VERSION 5.7 ;
  NOWIREEXTENSIONATPIN ON ;
  DIVIDERCHAR "/" ;
  BUSBITCHARS "[]" ;
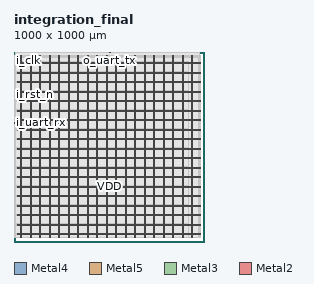
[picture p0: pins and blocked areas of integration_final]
MACRO integration_final
  CLASS BLOCK ;
  FOREIGN integration_final ;
  ORIGIN 0.000 0.000 ;
  SIZE 1000.000 BY 1000.000 ;
  PIN VDD
    DIRECTION INOUT ;
    USE POWER ;
    PORT
      LAYER Metal4 ;
        RECT 35.680 23.220 37.280 980.300 ;
    END
    PORT
      LAYER Metal4 ;
        RECT 85.680 23.220 87.280 980.300 ;
    END
    PORT
      LAYER Metal4 ;
        RECT 135.680 23.220 137.280 980.300 ;
    END
    PORT
      LAYER Metal4 ;
        RECT 185.680 23.220 187.280 980.300 ;
    END
    PORT
      LAYER Metal4 ;
        RECT 235.680 23.220 237.280 980.300 ;
    END
    PORT
      LAYER Metal4 ;
        RECT 285.680 23.220 287.280 980.300 ;
    END
    PORT
      LAYER Metal4 ;
        RECT 335.680 23.220 337.280 980.300 ;
    END
    PORT
      LAYER Metal4 ;
        RECT 385.680 23.220 387.280 980.300 ;
    END
    PORT
      LAYER Metal4 ;
        RECT 435.680 23.220 437.280 980.300 ;
    END
    PORT
      LAYER Metal4 ;
        RECT 485.680 23.220 487.280 980.300 ;
    END
    PORT
      LAYER Metal4 ;
        RECT 535.680 23.220 537.280 980.300 ;
    END
    PORT
      LAYER Metal4 ;
        RECT 585.680 23.220 587.280 980.300 ;
    END
    PORT
      LAYER Metal4 ;
        RECT 635.680 23.220 637.280 980.300 ;
    END
    PORT
      LAYER Metal4 ;
        RECT 685.680 23.220 687.280 980.300 ;
    END
    PORT
      LAYER Metal4 ;
        RECT 735.680 23.220 737.280 980.300 ;
    END
    PORT
      LAYER Metal4 ;
        RECT 785.680 23.220 787.280 980.300 ;
    END
    PORT
      LAYER Metal4 ;
        RECT 835.680 23.220 837.280 980.300 ;
    END
    PORT
      LAYER Metal4 ;
        RECT 885.680 23.220 887.280 980.300 ;
    END
    PORT
      LAYER Metal4 ;
        RECT 935.680 23.220 937.280 980.300 ;
    END
    PORT
      LAYER Metal5 ;
        RECT 20.160 39.370 980.000 40.970 ;
    END
    PORT
      LAYER Metal5 ;
        RECT 20.160 89.370 980.000 90.970 ;
    END
    PORT
      LAYER Metal5 ;
        RECT 20.160 139.370 980.000 140.970 ;
    END
    PORT
      LAYER Metal5 ;
        RECT 20.160 189.370 980.000 190.970 ;
    END
    PORT
      LAYER Metal5 ;
        RECT 20.160 239.370 980.000 240.970 ;
    END
    PORT
      LAYER Metal5 ;
        RECT 20.160 289.370 980.000 290.970 ;
    END
    PORT
      LAYER Metal5 ;
        RECT 20.160 339.370 980.000 340.970 ;
    END
    PORT
      LAYER Metal5 ;
        RECT 20.160 389.370 980.000 390.970 ;
    END
    PORT
      LAYER Metal5 ;
        RECT 20.160 439.370 980.000 440.970 ;
    END
    PORT
      LAYER Metal5 ;
        RECT 20.160 489.370 980.000 490.970 ;
    END
    PORT
      LAYER Metal5 ;
        RECT 20.160 539.370 980.000 540.970 ;
    END
    PORT
      LAYER Metal5 ;
        RECT 20.160 589.370 980.000 590.970 ;
    END
    PORT
      LAYER Metal5 ;
        RECT 20.160 639.370 980.000 640.970 ;
    END
    PORT
      LAYER Metal5 ;
        RECT 20.160 689.370 980.000 690.970 ;
    END
    PORT
      LAYER Metal5 ;
        RECT 20.160 739.370 980.000 740.970 ;
    END
    PORT
      LAYER Metal5 ;
        RECT 20.160 789.370 980.000 790.970 ;
    END
    PORT
      LAYER Metal5 ;
        RECT 20.160 839.370 980.000 840.970 ;
    END
    PORT
      LAYER Metal5 ;
        RECT 20.160 889.370 980.000 890.970 ;
    END
    PORT
      LAYER Metal5 ;
        RECT 20.160 939.370 980.000 940.970 ;
    END
  END VDD
  PIN VSS
    DIRECTION INOUT ;
    USE GROUND ;
    PORT
      LAYER Metal4 ;
        RECT 38.880 23.220 40.480 980.300 ;
    END
    PORT
      LAYER Metal4 ;
        RECT 88.880 23.220 90.480 980.300 ;
    END
    PORT
      LAYER Metal4 ;
        RECT 138.880 23.220 140.480 980.300 ;
    END
    PORT
      LAYER Metal4 ;
        RECT 188.880 23.220 190.480 980.300 ;
    END
    PORT
      LAYER Metal4 ;
        RECT 238.880 23.220 240.480 980.300 ;
    END
    PORT
      LAYER Metal4 ;
        RECT 288.880 23.220 290.480 980.300 ;
    END
    PORT
      LAYER Metal4 ;
        RECT 338.880 23.220 340.480 980.300 ;
    END
    PORT
      LAYER Metal4 ;
        RECT 388.880 23.220 390.480 980.300 ;
    END
    PORT
      LAYER Metal4 ;
        RECT 438.880 23.220 440.480 980.300 ;
    END
    PORT
      LAYER Metal4 ;
        RECT 488.880 23.220 490.480 980.300 ;
    END
    PORT
      LAYER Metal4 ;
        RECT 538.880 23.220 540.480 980.300 ;
    END
    PORT
      LAYER Metal4 ;
        RECT 588.880 23.220 590.480 980.300 ;
    END
    PORT
      LAYER Metal4 ;
        RECT 638.880 23.220 640.480 980.300 ;
    END
    PORT
      LAYER Metal4 ;
        RECT 688.880 23.220 690.480 980.300 ;
    END
    PORT
      LAYER Metal4 ;
        RECT 738.880 23.220 740.480 980.300 ;
    END
    PORT
      LAYER Metal4 ;
        RECT 788.880 23.220 790.480 980.300 ;
    END
    PORT
      LAYER Metal4 ;
        RECT 838.880 23.220 840.480 980.300 ;
    END
    PORT
      LAYER Metal4 ;
        RECT 888.880 23.220 890.480 980.300 ;
    END
    PORT
      LAYER Metal4 ;
        RECT 938.880 23.220 940.480 980.300 ;
    END
    PORT
      LAYER Metal5 ;
        RECT 20.160 42.570 980.000 44.170 ;
    END
    PORT
      LAYER Metal5 ;
        RECT 20.160 92.570 980.000 94.170 ;
    END
    PORT
      LAYER Metal5 ;
        RECT 20.160 142.570 980.000 144.170 ;
    END
    PORT
      LAYER Metal5 ;
        RECT 20.160 192.570 980.000 194.170 ;
    END
    PORT
      LAYER Metal5 ;
        RECT 20.160 242.570 980.000 244.170 ;
    END
    PORT
      LAYER Metal5 ;
        RECT 20.160 292.570 980.000 294.170 ;
    END
    PORT
      LAYER Metal5 ;
        RECT 20.160 342.570 980.000 344.170 ;
    END
    PORT
      LAYER Metal5 ;
        RECT 20.160 392.570 980.000 394.170 ;
    END
    PORT
      LAYER Metal5 ;
        RECT 20.160 442.570 980.000 444.170 ;
    END
    PORT
      LAYER Metal5 ;
        RECT 20.160 492.570 980.000 494.170 ;
    END
    PORT
      LAYER Metal5 ;
        RECT 20.160 542.570 980.000 544.170 ;
    END
    PORT
      LAYER Metal5 ;
        RECT 20.160 592.570 980.000 594.170 ;
    END
    PORT
      LAYER Metal5 ;
        RECT 20.160 642.570 980.000 644.170 ;
    END
    PORT
      LAYER Metal5 ;
        RECT 20.160 692.570 980.000 694.170 ;
    END
    PORT
      LAYER Metal5 ;
        RECT 20.160 742.570 980.000 744.170 ;
    END
    PORT
      LAYER Metal5 ;
        RECT 20.160 792.570 980.000 794.170 ;
    END
    PORT
      LAYER Metal5 ;
        RECT 20.160 842.570 980.000 844.170 ;
    END
    PORT
      LAYER Metal5 ;
        RECT 20.160 892.570 980.000 894.170 ;
    END
    PORT
      LAYER Metal5 ;
        RECT 20.160 942.570 980.000 944.170 ;
    END
  END VSS
  PIN i_clk
    DIRECTION INPUT ;
    USE SIGNAL ;
    ANTENNAGATEAREA 4.738000 ;
    ANTENNADIFFAREA 0.410400 ;
    PORT
      LAYER Metal3 ;
        RECT 0.000 974.400 0.560 974.960 ;
    END
  END i_clk
  PIN i_rst_n
    DIRECTION INPUT ;
    USE SIGNAL ;
    ANTENNAGATEAREA 1.183000 ;
    ANTENNADIFFAREA 0.410400 ;
    PORT
      LAYER Metal3 ;
        RECT 0.000 773.920 0.560 774.480 ;
    END
  END i_rst_n
  PIN i_uart_rx
    DIRECTION INPUT ;
    USE SIGNAL ;
    ANTENNAGATEAREA 0.741000 ;
    ANTENNADIFFAREA 0.410400 ;
    PORT
      LAYER Metal3 ;
        RECT 0.000 626.080 0.560 626.640 ;
    END
  END i_uart_rx
  PIN o_uart_tx
    DIRECTION OUTPUT ;
    USE SIGNAL ;
    ANTENNADIFFAREA 0.897600 ;
    PORT
      LAYER Metal2 ;
        RECT 505.120 999.440 505.680 1000.000 ;
    END
  END o_uart_tx
  OBS
      LAYER Nwell ;
        RECT 19.730 23.090 980.430 980.430 ;
      LAYER Metal1 ;
        RECT 20.160 23.220 980.000 980.300 ;
      LAYER Metal2 ;
        RECT 7.420 999.140 504.820 999.440 ;
        RECT 505.980 999.140 978.740 999.440 ;
        RECT 7.420 21.930 978.740 999.140 ;
      LAYER Metal3 ;
        RECT 0.560 975.260 978.790 980.140 ;
        RECT 0.860 974.100 978.790 975.260 ;
        RECT 0.560 774.780 978.790 974.100 ;
        RECT 0.860 773.620 978.790 774.780 ;
        RECT 0.560 626.940 978.790 773.620 ;
        RECT 0.860 625.780 978.790 626.940 ;
        RECT 0.560 21.980 978.790 625.780 ;
      LAYER Metal4 ;
        RECT 5.740 25.290 35.380 971.510 ;
        RECT 37.580 25.290 38.580 971.510 ;
        RECT 40.780 25.290 85.380 971.510 ;
        RECT 87.580 25.290 88.580 971.510 ;
        RECT 90.780 25.290 135.380 971.510 ;
        RECT 137.580 25.290 138.580 971.510 ;
        RECT 140.780 25.290 185.380 971.510 ;
        RECT 187.580 25.290 188.580 971.510 ;
        RECT 190.780 25.290 235.380 971.510 ;
        RECT 237.580 25.290 238.580 971.510 ;
        RECT 240.780 25.290 285.380 971.510 ;
        RECT 287.580 25.290 288.580 971.510 ;
        RECT 290.780 25.290 335.380 971.510 ;
        RECT 337.580 25.290 338.580 971.510 ;
        RECT 340.780 25.290 385.380 971.510 ;
        RECT 387.580 25.290 388.580 971.510 ;
        RECT 390.780 25.290 435.380 971.510 ;
        RECT 437.580 25.290 438.580 971.510 ;
        RECT 440.780 25.290 485.380 971.510 ;
        RECT 487.580 25.290 488.580 971.510 ;
        RECT 490.780 25.290 535.380 971.510 ;
        RECT 537.580 25.290 538.580 971.510 ;
        RECT 540.780 25.290 585.380 971.510 ;
        RECT 587.580 25.290 588.580 971.510 ;
        RECT 590.780 25.290 635.380 971.510 ;
        RECT 637.580 25.290 638.580 971.510 ;
        RECT 640.780 25.290 685.380 971.510 ;
        RECT 687.580 25.290 688.580 971.510 ;
        RECT 690.780 25.290 735.380 971.510 ;
        RECT 737.580 25.290 738.580 971.510 ;
        RECT 740.780 25.290 785.380 971.510 ;
        RECT 787.580 25.290 788.580 971.510 ;
        RECT 790.780 25.290 835.380 971.510 ;
        RECT 837.580 25.290 838.580 971.510 ;
        RECT 840.780 25.290 885.380 971.510 ;
        RECT 887.580 25.290 888.580 971.510 ;
        RECT 890.780 25.290 935.380 971.510 ;
        RECT 937.580 25.290 938.580 971.510 ;
        RECT 940.780 25.290 971.460 971.510 ;
      LAYER Metal5 ;
        RECT 5.660 944.770 919.460 949.270 ;
        RECT 5.660 941.970 19.560 944.770 ;
        RECT 5.660 941.570 919.460 941.970 ;
        RECT 5.660 938.770 19.560 941.570 ;
        RECT 5.660 894.770 919.460 938.770 ;
        RECT 5.660 891.970 19.560 894.770 ;
        RECT 5.660 891.570 919.460 891.970 ;
        RECT 5.660 888.770 19.560 891.570 ;
        RECT 5.660 844.770 919.460 888.770 ;
        RECT 5.660 841.970 19.560 844.770 ;
        RECT 5.660 841.570 919.460 841.970 ;
        RECT 5.660 838.770 19.560 841.570 ;
        RECT 5.660 794.770 919.460 838.770 ;
        RECT 5.660 791.970 19.560 794.770 ;
        RECT 5.660 791.570 919.460 791.970 ;
        RECT 5.660 788.770 19.560 791.570 ;
        RECT 5.660 744.770 919.460 788.770 ;
        RECT 5.660 741.970 19.560 744.770 ;
        RECT 5.660 741.570 919.460 741.970 ;
        RECT 5.660 738.770 19.560 741.570 ;
        RECT 5.660 694.770 919.460 738.770 ;
        RECT 5.660 691.970 19.560 694.770 ;
        RECT 5.660 691.570 919.460 691.970 ;
        RECT 5.660 688.770 19.560 691.570 ;
        RECT 5.660 644.770 919.460 688.770 ;
        RECT 5.660 641.970 19.560 644.770 ;
        RECT 5.660 641.570 919.460 641.970 ;
        RECT 5.660 638.770 19.560 641.570 ;
        RECT 5.660 594.770 919.460 638.770 ;
        RECT 5.660 591.970 19.560 594.770 ;
        RECT 5.660 591.570 919.460 591.970 ;
        RECT 5.660 588.770 19.560 591.570 ;
        RECT 5.660 544.770 919.460 588.770 ;
        RECT 5.660 541.970 19.560 544.770 ;
        RECT 5.660 541.570 919.460 541.970 ;
        RECT 5.660 538.770 19.560 541.570 ;
        RECT 5.660 494.770 919.460 538.770 ;
        RECT 5.660 491.970 19.560 494.770 ;
        RECT 5.660 491.570 919.460 491.970 ;
        RECT 5.660 488.770 19.560 491.570 ;
        RECT 5.660 444.770 919.460 488.770 ;
        RECT 5.660 441.970 19.560 444.770 ;
        RECT 5.660 441.570 919.460 441.970 ;
        RECT 5.660 438.770 19.560 441.570 ;
        RECT 5.660 394.770 919.460 438.770 ;
        RECT 5.660 391.970 19.560 394.770 ;
        RECT 5.660 391.570 919.460 391.970 ;
        RECT 5.660 388.770 19.560 391.570 ;
        RECT 5.660 344.770 919.460 388.770 ;
        RECT 5.660 341.970 19.560 344.770 ;
        RECT 5.660 341.570 919.460 341.970 ;
        RECT 5.660 338.770 19.560 341.570 ;
        RECT 5.660 294.770 919.460 338.770 ;
        RECT 5.660 291.970 19.560 294.770 ;
        RECT 5.660 291.570 919.460 291.970 ;
        RECT 5.660 288.770 19.560 291.570 ;
        RECT 5.660 244.770 919.460 288.770 ;
        RECT 5.660 241.970 19.560 244.770 ;
        RECT 5.660 241.570 919.460 241.970 ;
        RECT 5.660 238.770 19.560 241.570 ;
        RECT 5.660 194.770 919.460 238.770 ;
        RECT 5.660 191.970 19.560 194.770 ;
        RECT 5.660 191.570 919.460 191.970 ;
        RECT 5.660 188.770 19.560 191.570 ;
        RECT 5.660 144.770 919.460 188.770 ;
        RECT 5.660 141.970 19.560 144.770 ;
        RECT 5.660 141.570 919.460 141.970 ;
        RECT 5.660 138.770 19.560 141.570 ;
        RECT 5.660 94.770 919.460 138.770 ;
        RECT 5.660 91.970 19.560 94.770 ;
        RECT 5.660 91.570 919.460 91.970 ;
        RECT 5.660 88.770 19.560 91.570 ;
        RECT 5.660 44.770 919.460 88.770 ;
        RECT 5.660 41.970 19.560 44.770 ;
        RECT 5.660 41.570 919.460 41.970 ;
        RECT 5.660 38.770 19.560 41.570 ;
        RECT 5.660 25.430 919.460 38.770 ;
  END
END integration_final
END LIBRARY

